VERSION 5.7 ;
  NOWIREEXTENSIONATPIN ON ;
  DIVIDERCHAR "/" ;
  BUSBITCHARS "[]" ;
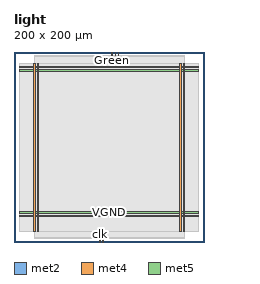
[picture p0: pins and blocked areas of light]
MACRO light
  CLASS BLOCK ;
  FOREIGN light ;
  ORIGIN 0.000 0.000 ;
  SIZE 200.000 BY 200.000 ;
  PIN Green
    DIRECTION OUTPUT TRISTATE ;
    USE SIGNAL ;
    ANTENNADIFFAREA 0.795200 ;
    PORT
      LAYER met2 ;
        RECT 103.130 196.000 103.410 200.000 ;
    END
  END Green
  PIN Red
    DIRECTION OUTPUT TRISTATE ;
    USE SIGNAL ;
    ANTENNADIFFAREA 0.795200 ;
    PORT
      LAYER met2 ;
        RECT 106.350 196.000 106.630 200.000 ;
    END
  END Red
  PIN VGND
    DIRECTION INOUT ;
    USE GROUND ;
    PORT
      LAYER met4 ;
        RECT 24.340 10.640 25.940 187.920 ;
    END
    PORT
      LAYER met4 ;
        RECT 177.940 10.640 179.540 187.920 ;
    END
    PORT
      LAYER met5 ;
        RECT 5.280 30.030 194.360 31.630 ;
    END
    PORT
      LAYER met5 ;
        RECT 5.280 183.210 194.360 184.810 ;
    END
  END VGND
  PIN VPWR
    DIRECTION INOUT ;
    USE POWER ;
    PORT
      LAYER met4 ;
        RECT 21.040 10.640 22.640 187.920 ;
    END
    PORT
      LAYER met4 ;
        RECT 174.640 10.640 176.240 187.920 ;
    END
    PORT
      LAYER met5 ;
        RECT 5.280 26.730 194.360 28.330 ;
    END
    PORT
      LAYER met5 ;
        RECT 5.280 179.910 194.360 181.510 ;
    END
  END VPWR
  PIN Yellow
    DIRECTION OUTPUT TRISTATE ;
    USE SIGNAL ;
    ANTENNADIFFAREA 0.795200 ;
    PORT
      LAYER met2 ;
        RECT 109.570 196.000 109.850 200.000 ;
    END
  END Yellow
  PIN clk
    DIRECTION INPUT ;
    USE SIGNAL ;
    ANTENNAGATEAREA 0.852000 ;
    PORT
      LAYER met2 ;
        RECT 90.250 0.000 90.530 4.000 ;
    END
  END clk
  PIN rst
    DIRECTION INPUT ;
    USE SIGNAL ;
    ANTENNAGATEAREA 0.126000 ;
    PORT
      LAYER met2 ;
        RECT 93.470 0.000 93.750 4.000 ;
    END
  END rst
  OBS
      LAYER li1 ;
        RECT 5.520 10.795 194.120 187.765 ;
      LAYER met1 ;
        RECT 5.520 10.640 194.120 187.920 ;
      LAYER met2 ;
        RECT 21.070 195.720 102.850 196.000 ;
        RECT 103.690 195.720 106.070 196.000 ;
        RECT 106.910 195.720 109.290 196.000 ;
        RECT 110.130 195.720 179.510 196.000 ;
        RECT 21.070 4.280 179.510 195.720 ;
        RECT 21.070 4.000 89.970 4.280 ;
        RECT 90.810 4.000 93.190 4.280 ;
        RECT 94.030 4.000 179.510 4.280 ;
      LAYER met3 ;
        RECT 21.050 10.715 179.530 187.845 ;
  END
END light
END LIBRARY

